VERSION 5.8 ;
BUSBITCHARS "[]" ;
DIVIDERCHAR "/" ;
SITE core_site
  CLASS CORE ;
  SYMMETRY Y ;
  SIZE 0.1 BY 1.0 ;
END core_site
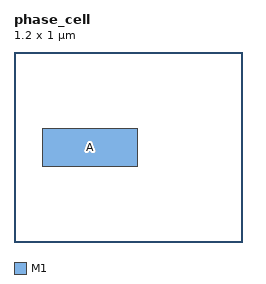
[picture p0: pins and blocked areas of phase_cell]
MACRO phase_cell
  CLASS CORE ;
  ORIGIN 0 0 ;
  SIZE 1.2 BY 1.0 ;
  SYMMETRY X Y ;
  SITE core_site ;
  PIN A
    DIRECTION INPUT ;
    USE SIGNAL ;
    PORT
      LAYER M1 ;
        RECT 0.15 0.4 0.65 0.6 ;
    END
  END A
END phase_cell
END LIBRARY
